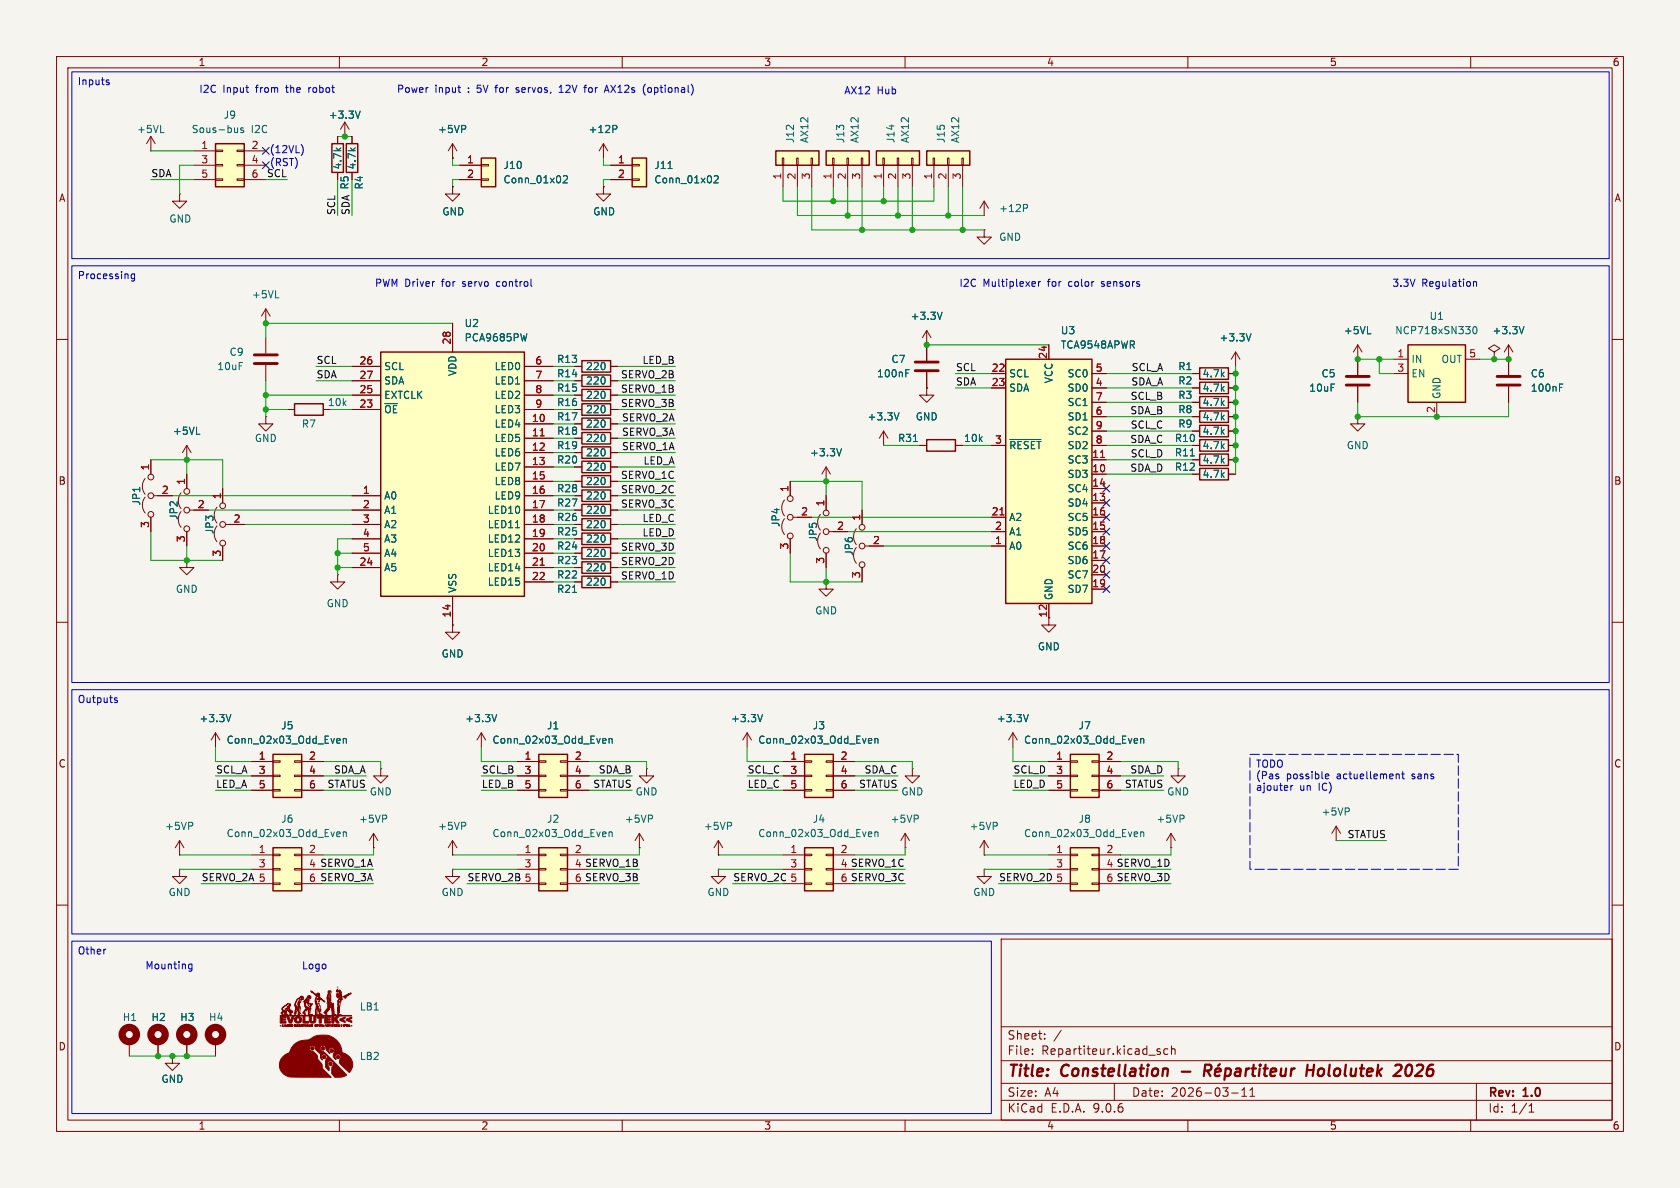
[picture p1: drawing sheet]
<svg xmlns="http://www.w3.org/2000/svg" width="297mm" height="210mm" viewBox="0 0 297 210" stroke-linecap="round" stroke-linejoin="round" font-family="sans-serif">
<defs><g id="words">
<g font-size="2.8" fill="#840000">
<text x="178" y="190.9">Title:</text>
<text x="187.7" y="190.9">Constellation</text>
<text x="233.4" y="190.9">Hololutek</text>
<text x="249.8" y="190.9">2026</text>
</g>
<g font-size="2.1" fill="#840000">
<text x="178" y="184">Sheet:</text>
<text x="178" y="186.7">File:</text>
<text x="184.1" y="186.7">Repartiteur.kicad_sch</text>
<text x="178" y="196.9">KiCad</text>
<text x="178" y="194.1">Size:</text>
<text x="184.7" y="194.1">A4</text>
<text x="185.7" y="196.9">E.D.A.</text>
<text x="193.3" y="196.9">9.0.6</text>
<text x="200" y="194.1">Date:</text>
<text x="207" y="194.1">2026-03-11</text>
<text x="263" y="194.3">Rev:</text>
<text x="263" y="196.9">Id:</text>
<text x="267.1" y="196.9">1/1</text>
<text x="269.4" y="194.3">1.0</text>
</g>
<g font-size="1.8" fill="#840000">
<text x="35" y="11.9">1</text>
<text x="85" y="11.9">2</text>
<text x="135" y="11.9">3</text>
<text x="185" y="11.9">4</text>
<text x="235" y="11.9">5</text>
<text x="285" y="11.9">6</text>
<text x="10.3" y="35.9">A</text>
<text x="285.3" y="35.9">A</text>
<text x="10.3" y="85.9">B</text>
<text x="285.3" y="85.9">B</text>
<text x="10.3" y="135.9">C</text>
<text x="285.3" y="135.9">C</text>
<text x="10.3" y="185.9">D</text>
<text x="285.3" y="185.9">D</text>
<text x="35" y="199.9">1</text>
<text x="85" y="199.9">2</text>
<text x="135" y="199.9">3</text>
<text x="185" y="199.9">4</text>
<text x="235" y="199.9">5</text>
<text x="285" y="199.9">6</text>
</g>
<g font-size="1.8" fill="#0000c2">
<text x="13.7" y="15.4">Inputs</text>
<text x="35.1" y="16.6">I2C</text>
<text x="39.4" y="16.6">Input</text>
<text x="45.3" y="16.6">from</text>
<text x="50.9" y="16.6">the</text>
<text x="55" y="16.6">robot</text>
<text x="70.1" y="16.6">Power</text>
<text x="76.9" y="16.6">input</text>
<text x="82.8" y="16.6">:</text>
<text x="84.6" y="16.6">5V</text>
<text x="88.1" y="16.6">for</text>
<text x="91.9" y="16.6">servos,</text>
<text x="99.7" y="16.6">12V</text>
<text x="104.4" y="16.6">for</text>
<text x="108.2" y="16.6">AX12s</text>
<text x="115.2" y="16.6">(optional)</text>
<text x="149.2" y="16.9">AX12</text>
<text x="155.1" y="16.9">Hub</text>
<text x="47.6" y="27.3">(12VL)</text>
<text x="47.6" y="29.6">(RST)</text>
<text x="47.1" y="31.4">SCL</text>
<text x="13.7" y="49.7">Processing</text>
<text x="66.2" y="50.9">PWM Driver</text>
<text x="78.2" y="50.9">for</text>
<text x="82" y="50.9">servo</text>
<text x="88.2" y="50.9">control</text>
<text x="169.5" y="50.9">I2C</text>
<text x="173.8" y="50.9">Multiplexer</text>
<text x="185.3" y="50.9">for</text>
<text x="189.2" y="50.9">color</text>
<text x="195.2" y="50.9">sensors</text>
<text x="246.1" y="50.9">3.3V</text>
<text x="251.3" y="50.9">Regulation</text>
<text x="13.7" y="124.6">Outputs</text>
<text x="221.9" y="136">TODO</text>
<text x="221.9" y="138.1">(Pas</text>
<text x="221.9" y="140.1">ajouter</text>
<text x="227.4" y="138.1">possible</text>
<text x="229.8" y="140.1">un</text>
<text x="233.2" y="140.1">IC)</text>
<text x="236.4" y="138.1">actuellement</text>
<text x="249.9" y="138.1">sans</text>
<text x="13.7" y="169">Other</text>
<text x="25.6" y="171.6">Mounting</text>
<text x="53.3" y="171.6">Logo</text>
</g>
<g font-size="1.8" fill="#006464">
<text x="24.1" y="23.7">+5VL</text>
<text x="33.8" y="23.7">Sous-bus</text>
<text x="39.4" y="21.2">J9</text>
<text x="44.4" y="23.7">I2C</text>
<text x="58" y="21.2">+3.3V</text>
<text x="77.3" y="23.7">+5VP</text>
<text x="103.9" y="23.7">+12P</text>
<text x="140.6" y="25.4" transform="rotate(-90 140.6 25.4)">J12</text>
<text x="143.1" y="25.4" transform="rotate(-90 143.1 25.4)">AX12</text>
<text x="149.5" y="25.4" transform="rotate(-90 149.5 25.4)">J13</text>
<text x="152" y="25.4" transform="rotate(-90 152 25.4)">AX12</text>
<text x="158.3" y="25.4" transform="rotate(-90 158.3 25.4)">J14</text>
<text x="160.9" y="25.4" transform="rotate(-90 160.9 25.4)">AX12</text>
<text x="167.2" y="25.4" transform="rotate(-90 167.2 25.4)">J15</text>
<text x="169.8" y="25.4" transform="rotate(-90 169.8 25.4)">AX12</text>
<text x="60.6" y="30.1" transform="rotate(-90 60.6 30.1)">4.7k</text>
<text x="61.8" y="33.6" transform="rotate(-90 61.8 33.6)">R5</text>
<text x="63.1" y="30.1" transform="rotate(-90 63.1 30.1)">4.7k</text>
<text x="64.4" y="33.6" transform="rotate(-90 64.4 33.6)">R4</text>
<text x="88.9" y="32.6">Conn_01x02</text>
<text x="88.9" y="30.1">J10</text>
<text x="115.6" y="32.6">Conn_01x02</text>
<text x="115.6" y="30.1">J11</text>
<text x="29.8" y="39.5">GND</text>
<text x="78.1" y="38.3">GND</text>
<text x="104.8" y="38.3">GND</text>
<text x="176.5" y="37.7">+12P</text>
<text x="176.5" y="42.8">GND</text>
<text x="44.4" y="52.9">+5VL</text>
<text x="82" y="58">U2</text>
<text x="160.9" y="56.7">+3.3V</text>
<text x="187.4" y="59.3">U3</text>
<text x="237.5" y="59.3">+5VL</text>
<text x="246.6" y="59.3">NCP718xSN330</text>
<text x="252.6" y="56.7">U1</text>
<text x="263.8" y="59.3">+3.3V</text>
<text x="38.3" y="65.6">10uF</text>
<text x="40.5" y="63.1">C9</text>
<text x="67.8" y="65.6">SCL</text>
<text x="82" y="60.6">PCA9685PW</text>
<text x="87.3" y="65.6">LED0</text>
<text x="98.4" y="64.4">R13</text>
<text x="103.5" y="65.6">220</text>
<text x="157.5" y="64.4">C7</text>
<text x="187.4" y="61.8">TCA9548APWR</text>
<text x="208.2" y="65.6">R1</text>
<text x="215.5" y="60.6">+3.3V</text>
<text x="249.4" y="64.4">IN</text>
<text x="254.7" y="64.4">OUT</text>
<text x="57.9" y="72">10k</text>
<text x="67.8" y="68.2">SDA</text>
<text x="67.8" y="70.7">EXTCLK</text>
<text x="80.9" y="66.6" transform="rotate(-90 80.9 66.6)">VDD</text>
<text x="87.3" y="68.2">LED1</text>
<text x="87.3" y="70.7">LED2</text>
<text x="98.4" y="69.4">R15</text>
<text x="98.4" y="66.9">R14</text>
<text x="98.4" y="72">R16</text>
<text x="103.5" y="70.7">220</text>
<text x="103.5" y="68.2">220</text>
<text x="154.9" y="66.9">100nF</text>
<text x="178.3" y="66.9">SCL</text>
<text x="178.3" y="69.4">SDA</text>
<text x="186.3" y="67.8" transform="rotate(-90 186.3 67.8)">VCC</text>
<text x="188.6" y="66.9">SC0</text>
<text x="188.6" y="69.4">SD0</text>
<text x="188.6" y="72">SC1</text>
<text x="208.2" y="70.7">R3</text>
<text x="208.2" y="68.2">R2</text>
<text x="212.5" y="72">4.7k</text>
<text x="212.5" y="69.4">4.7k</text>
<text x="212.5" y="66.9">4.7k</text>
<text x="231.4" y="69.4">10uF</text>
<text x="233.5" y="66.9">C5</text>
<text x="249.4" y="66.9">EN</text>
<text x="254.9" y="70.6" transform="rotate(-90 254.9 70.6)">GND</text>
<text x="270.5" y="66.9">C6</text>
<text x="270.5" y="69.4">100nF</text>
<text x="30.5" y="77.1">+5VL</text>
<text x="53.3" y="75.8">R7</text>
<text x="67.8" y="73.3">~{OE}</text>
<text x="87.3" y="73.3">LED3</text>
<text x="87.3" y="75.8">LED4</text>
<text x="98.4" y="74.5">R17</text>
<text x="98.4" y="77.1">R18</text>
<text x="103.5" y="75.8">220</text>
<text x="103.5" y="73.3">220</text>
<text x="153.3" y="74.5">+3.3V</text>
<text x="161.8" y="74.5">GND</text>
<text x="188.6" y="74.5">SD1</text>
<text x="188.6" y="77.1">SC2</text>
<text x="208.2" y="75.8">R9</text>
<text x="208.2" y="73.3">R8</text>
<text x="212.5" y="77.1">4.7k</text>
<text x="212.5" y="74.5">4.7k</text>
<text x="45" y="78.3">GND</text>
<text x="87.3" y="78.3">LED5</text>
<text x="87.3" y="80.9">LED6</text>
<text x="87.3" y="83.4">LED7</text>
<text x="98.4" y="82.1">R20</text>
<text x="98.4" y="79.6">R19</text>
<text x="103.5" y="83.4">220</text>
<text x="103.5" y="80.9">220</text>
<text x="103.5" y="78.3">220</text>
<text x="143.1" y="80.9">+3.3V</text>
<text x="158.7" y="78.3">R31</text>
<text x="170.3" y="78.3">10k</text>
<text x="178.3" y="79.6">~{RESET}</text>
<text x="188.6" y="79.6">SD2</text>
<text x="188.6" y="82.1">SC3</text>
<text x="207.6" y="80.9">R11</text>
<text x="207.6" y="83.4">R12</text>
<text x="207.6" y="78.3">R10</text>
<text x="212.5" y="82.1">4.7k</text>
<text x="212.5" y="79.6">4.7k</text>
<text x="238" y="79.6">GND</text>
<text x="25" y="89.5" transform="rotate(-90 25 89.5)">JP1</text>
<text x="67.8" y="88.5">A0</text>
<text x="87.3" y="86">LED8</text>
<text x="87.3" y="88.5">LED9</text>
<text x="98.4" y="87.2">R28</text>
<text x="98.4" y="89.8">R27</text>
<text x="103.5" y="86">220</text>
<text x="103.5" y="88.5">220</text>
<text x="188.6" y="84.7">SD3</text>
<text x="188.6" y="87.2">SC4</text>
<text x="188.6" y="89.8">SD4</text>
<text x="212.5" y="84.7">4.7k</text>
<text x="31.6" y="92" transform="rotate(-90 31.6 92)">JP2</text>
<text x="37.9" y="94.5" transform="rotate(-90 37.9 94.5)">JP3</text>
<text x="67.8" y="91">A1</text>
<text x="67.8" y="93.6">A2</text>
<text x="86.1" y="91">LED10</text>
<text x="86.1" y="93.6">LED11</text>
<text x="98.4" y="92.3">R26</text>
<text x="98.4" y="94.8">R25</text>
<text x="103.5" y="91">220</text>
<text x="103.5" y="93.6">220</text>
<text x="138" y="93.3" transform="rotate(-90 138 93.3)">JP4</text>
<text x="144.6" y="95.8" transform="rotate(-90 144.6 95.8)">JP5</text>
<text x="178.3" y="92.3">A2</text>
<text x="178.3" y="94.8">A1</text>
<text x="188.6" y="92.3">SC5</text>
<text x="188.6" y="94.8">SD5</text>
<text x="67.8" y="96.1">A3</text>
<text x="67.8" y="98.7">A4</text>
<text x="67.8" y="101.2">A5</text>
<text x="86.1" y="96.1">LED12</text>
<text x="86.1" y="98.7">LED13</text>
<text x="86.1" y="101.2">LED14</text>
<text x="98.4" y="99.9">R23</text>
<text x="98.4" y="97.4">R24</text>
<text x="103.5" y="101.2">220</text>
<text x="103.5" y="98.7">220</text>
<text x="103.5" y="96.1">220</text>
<text x="151" y="98.3" transform="rotate(-90 151 98.3)">JP6</text>
<text x="178.3" y="97.4">A0</text>
<text x="188.6" y="97.4">SC6</text>
<text x="188.6" y="99.9">SD6</text>
<text x="31" y="105">GND</text>
<text x="57.7" y="107.5">GND</text>
<text x="80.9" y="104.9" transform="rotate(-90 80.9 104.9)">VSS</text>
<text x="86.1" y="103.7">LED15</text>
<text x="98.4" y="105">R21</text>
<text x="98.4" y="102.5">R22</text>
<text x="103.5" y="103.7">220</text>
<text x="186.3" y="106.2" transform="rotate(-90 186.3 106.2)">GND</text>
<text x="188.6" y="102.5">SC7</text>
<text x="188.6" y="105">SD7</text>
<text x="144" y="108.8">GND</text>
<text x="78" y="116.4">GND</text>
<text x="183.4" y="115.2">GND</text>
<text x="35.2" y="127.9">+3.3V</text>
<text x="40" y="131.7">Conn_02x03_Odd_Even</text>
<text x="49.6" y="129.1">J5</text>
<text x="82.1" y="127.9">+3.3V</text>
<text x="87" y="131.7">Conn_02x03_Odd_Even</text>
<text x="96.6" y="129.1">J1</text>
<text x="129.1" y="127.9">+3.3V</text>
<text x="133.9" y="131.7">Conn_02x03_Odd_Even</text>
<text x="143.6" y="129.1">J3</text>
<text x="176.1" y="127.9">+3.3V</text>
<text x="180.9" y="131.7">Conn_02x03_Odd_Even</text>
<text x="190.6" y="129.1">J7</text>
<text x="65.3" y="140.8">GND</text>
<text x="112.3" y="140.8">GND</text>
<text x="159.3" y="140.8">GND</text>
<text x="206.2" y="140.8">GND</text>
<text x="29.1" y="146.9">+5VP</text>
<text x="40" y="148.2">Conn_02x03_Odd_Even</text>
<text x="49.6" y="145.6">J6</text>
<text x="63.4" y="145.6">+5VP</text>
<text x="77.3" y="146.9">+5VP</text>
<text x="87" y="148.2">Conn_02x03_Odd_Even</text>
<text x="96.6" y="145.6">J2</text>
<text x="110.4" y="145.6">+5VP</text>
<text x="124.3" y="146.9">+5VP</text>
<text x="133.9" y="148.2">Conn_02x03_Odd_Even</text>
<text x="143.6" y="145.6">J4</text>
<text x="157.3" y="145.6">+5VP</text>
<text x="171.3" y="146.9">+5VP</text>
<text x="180.9" y="148.2">Conn_02x03_Odd_Even</text>
<text x="190.6" y="145.6">J8</text>
<text x="204.3" y="145.6">+5VP</text>
<text x="233.5" y="144.4">+5VP</text>
<text x="29.7" y="158.6">GND</text>
<text x="78" y="158.6">GND</text>
<text x="125" y="158.6">GND</text>
<text x="172" y="158.6">GND</text>
<text x="63.5" y="178.8">LB1</text>
<text x="21.6" y="180.7">H1</text>
<text x="26.7" y="180.7">H2</text>
<text x="31.8" y="180.7">H3</text>
<text x="36.8" y="180.7">H4</text>
<text x="28.4" y="191.6">GND</text>
<text x="63.5" y="187.6">LB2</text>
</g>
<g font-size="1.8" fill="#a90000">
<text x="35.5" y="26.4">1</text>
<text x="35.5" y="29">3</text>
<text x="44.4" y="26.4">2</text>
<text x="44.4" y="29">4</text>
<text x="82.5" y="29">1</text>
<text x="109.1" y="29">1</text>
<text x="35.5" y="31.5">5</text>
<text x="44.4" y="31.5">6</text>
<text x="82.5" y="31.5">2</text>
<text x="109.1" y="31.5">2</text>
<text x="138.2" y="31.8" transform="rotate(-90 138.2 31.8)">1</text>
<text x="140.7" y="31.8" transform="rotate(-90 140.7 31.8)">2</text>
<text x="143.3" y="31.8" transform="rotate(-90 143.3 31.8)">3</text>
<text x="147.1" y="31.8" transform="rotate(-90 147.1 31.8)">1</text>
<text x="149.6" y="31.8" transform="rotate(-90 149.6 31.8)">2</text>
<text x="152.1" y="31.8" transform="rotate(-90 152.1 31.8)">3</text>
<text x="156" y="31.8" transform="rotate(-90 156 31.8)">1</text>
<text x="158.5" y="31.8" transform="rotate(-90 158.5 31.8)">2</text>
<text x="161" y="31.8" transform="rotate(-90 161 31.8)">3</text>
<text x="164.8" y="31.8" transform="rotate(-90 164.8 31.8)">1</text>
<text x="167.4" y="31.8" transform="rotate(-90 167.4 31.8)">2</text>
<text x="169.9" y="31.8" transform="rotate(-90 169.9 31.8)">3</text>
<text x="63.5" y="64.5">26</text>
<text x="79.8" y="61" transform="rotate(-90 79.8 61)">28</text>
<text x="94.5" y="64.5">6</text>
<text x="175.2" y="65.8">22</text>
<text x="185.2" y="63.5" transform="rotate(-90 185.2 63.5)">24</text>
<text x="193.6" y="65.8">5</text>
<text x="246.9" y="63.2">1</text>
<text x="246.9" y="65.8">3</text>
<text x="259.6" y="63.2">5</text>
<text x="63.5" y="67.1">27</text>
<text x="63.5" y="69.6">25</text>
<text x="94.5" y="67.1">7</text>
<text x="94.5" y="69.6">8</text>
<text x="175.2" y="68.3">23</text>
<text x="193.6" y="68.3">4</text>
<text x="193.6" y="70.9">7</text>
<text x="63.5" y="72.1">23</text>
<text x="93.9" y="74.7">10</text>
<text x="93.9" y="77.2">11</text>
<text x="94.5" y="72.1">9</text>
<text x="193.6" y="73.4">6</text>
<text x="193.6" y="75.9">9</text>
<text x="253.7" y="73.1" transform="rotate(-90 253.7 73.1)">2</text>
<text x="26.4" y="83.3" transform="rotate(-90 26.4 83.3)">1</text>
<text x="93.9" y="79.8">12</text>
<text x="93.9" y="82.3">13</text>
<text x="175.8" y="78.5">3</text>
<text x="193" y="81">11</text>
<text x="193" y="83.6">10</text>
<text x="193.6" y="78.5">8</text>
<text x="28.5" y="87.4">2</text>
<text x="32.8" y="85.8" transform="rotate(-90 32.8 85.8)">1</text>
<text x="34.9" y="89.9">2</text>
<text x="39.1" y="88.3" transform="rotate(-90 39.1 88.3)">1</text>
<text x="64.1" y="87.4">1</text>
<text x="64.1" y="89.9">2</text>
<text x="93.9" y="84.8">15</text>
<text x="93.9" y="87.4">16</text>
<text x="93.9" y="89.9">17</text>
<text x="139.4" y="87.1" transform="rotate(-90 139.4 87.1)">1</text>
<text x="145.8" y="89.6" transform="rotate(-90 145.8 89.6)">1</text>
<text x="193" y="86.1">14</text>
<text x="193" y="88.6">13</text>
<text x="26.4" y="93.4" transform="rotate(-90 26.4 93.4)">3</text>
<text x="32.8" y="96" transform="rotate(-90 32.8 96)">3</text>
<text x="41.2" y="92.5">2</text>
<text x="64.1" y="92.5">3</text>
<text x="64.1" y="95">4</text>
<text x="93.9" y="92.5">18</text>
<text x="93.9" y="95">19</text>
<text x="141.5" y="91.2">2</text>
<text x="147.9" y="93.7">2</text>
<text x="152.1" y="92.1" transform="rotate(-90 152.1 92.1)">1</text>
<text x="175.2" y="91.2">21</text>
<text x="175.8" y="93.7">2</text>
<text x="193" y="91.2">16</text>
<text x="193" y="93.7">15</text>
<text x="39.1" y="98.5" transform="rotate(-90 39.1 98.5)">3</text>
<text x="63.5" y="100.1">24</text>
<text x="64.1" y="97.5">5</text>
<text x="93.9" y="97.5">20</text>
<text x="93.9" y="100.1">21</text>
<text x="139.4" y="97.2" transform="rotate(-90 139.4 97.2)">3</text>
<text x="145.8" y="99.8" transform="rotate(-90 145.8 99.8)">3</text>
<text x="154.2" y="96.3">2</text>
<text x="175.8" y="96.3">1</text>
<text x="193" y="96.3">18</text>
<text x="193" y="98.8">17</text>
<text x="193" y="101.3">20</text>
<text x="93.9" y="102.6">22</text>
<text x="152.1" y="102.3" transform="rotate(-90 152.1 102.3)">3</text>
<text x="193" y="103.9">19</text>
<text x="79.8" y="109.3" transform="rotate(-90 79.8 109.3)">14</text>
<text x="185.2" y="109.3" transform="rotate(-90 185.2 109.3)">12</text>
<text x="45.6" y="134.4">1</text>
<text x="45.6" y="136.9">3</text>
<text x="54.5" y="134.4">2</text>
<text x="54.5" y="136.9">4</text>
<text x="92.6" y="134.4">1</text>
<text x="92.6" y="136.9">3</text>
<text x="101.5" y="134.4">2</text>
<text x="101.5" y="136.9">4</text>
<text x="139.6" y="134.4">1</text>
<text x="139.6" y="136.9">3</text>
<text x="148.5" y="134.4">2</text>
<text x="148.5" y="136.9">4</text>
<text x="186.6" y="134.4">1</text>
<text x="186.6" y="136.9">3</text>
<text x="195.5" y="134.4">2</text>
<text x="195.5" y="136.9">4</text>
<text x="45.6" y="139.4">5</text>
<text x="54.5" y="139.4">6</text>
<text x="92.6" y="139.4">5</text>
<text x="101.5" y="139.4">6</text>
<text x="139.6" y="139.4">5</text>
<text x="148.5" y="139.4">6</text>
<text x="186.6" y="139.4">5</text>
<text x="195.5" y="139.4">6</text>
<text x="45.6" y="150.9">1</text>
<text x="45.6" y="153.4">3</text>
<text x="54.5" y="150.9">2</text>
<text x="92.6" y="150.9">1</text>
<text x="92.6" y="153.4">3</text>
<text x="101.5" y="150.9">2</text>
<text x="139.6" y="150.9">1</text>
<text x="139.6" y="153.4">3</text>
<text x="148.5" y="150.9">2</text>
<text x="186.6" y="150.9">1</text>
<text x="186.6" y="153.4">3</text>
<text x="195.5" y="150.9">2</text>
</g>
<g font-size="1.8" fill="#0f0f0f">
<text x="26.7" y="31.4">SDA</text>
<text x="59.3" y="38.1" transform="rotate(-90 59.3 38.1)">SCL</text>
<text x="61.9" y="38.1" transform="rotate(-90 61.9 38.1)">SDA R5</text>
<text x="55.9" y="64.4">SCL</text>
<text x="113.5" y="64.4">LED_B</text>
<text x="168.9" y="65.7">SCL</text>
<text x="200" y="65.7">SCL_A</text>
<text x="55.9" y="67">SDA</text>
<text x="109.7" y="69.5">SERVO_1B</text>
<text x="109.7" y="67">SERVO_2B</text>
<text x="168.9" y="68.2">SDA</text>
<text x="199.8" y="70.8">SCL_B</text>
<text x="199.9" y="68.2">SDA_A</text>
<text x="109.7" y="72">SERVO_3B</text>
<text x="109.9" y="77.1">SERVO_3A</text>
<text x="109.9" y="74.6">SERVO_2A</text>
<text x="199.7" y="73.3">SDA_B</text>
<text x="199.8" y="75.9">SCL_C</text>
<text x="109.9" y="79.7">SERVO_1A</text>
<text x="113.7" y="82.2">LED_A</text>
<text x="199.7" y="83.5">SDA_D</text>
<text x="199.7" y="78.4">SDA_C</text>
<text x="199.8" y="80.9">SCL_D</text>
<text x="109.7" y="89.8">SERVO_3C</text>
<text x="109.7" y="84.7">SERVO_1C</text>
<text x="109.7" y="87.3">SERVO_2C</text>
<text x="113.5" y="92.4">LED_C</text>
<text x="113.5" y="94.9">LED_D</text>
<text x="109.7" y="97.4">SERVO_3D</text>
<text x="109.7" y="100">SERVO_2D</text>
<text x="109.7" y="102.5">SERVO_1D</text>
<text x="38.1" y="136.8">SCL_A</text>
<text x="58.9" y="136.8">SDA_A</text>
<text x="85.1" y="136.8">SCL_B</text>
<text x="105.8" y="136.8">SDA_B</text>
<text x="132.1" y="136.8">SCL_C</text>
<text x="152.7" y="136.8">SDA_C</text>
<text x="179.1" y="136.8">SCL_D</text>
<text x="199.7" y="136.8">SDA_D</text>
<text x="38.1" y="139.4">LED_A</text>
<text x="57.8" y="139.4">STATUS</text>
<text x="85.1" y="139.4">LED_B</text>
<text x="104.8" y="139.4">STATUS</text>
<text x="132.1" y="139.4">LED_C</text>
<text x="151.8" y="139.4">STATUS</text>
<text x="179.1" y="139.4">LED_D</text>
<text x="198.8" y="139.4">STATUS</text>
<text x="238.1" y="148.2">STATUS</text>
<text x="35.6" y="155.9">SERVO_2A 5</text>
<text x="54.5" y="153.4">4 SERVO_1A</text>
<text x="54.5" y="156">6 SERVO_3A</text>
<text x="82.5" y="155.9">SERVO_2B 5</text>
<text x="101.5" y="153.4">4 SERVO_1B</text>
<text x="101.5" y="156">6 SERVO_3B</text>
<text x="129.5" y="155.9">SERVO_2C 5</text>
<text x="148.5" y="153.4">4 SERVO_1C</text>
<text x="148.5" y="156">6 SERVO_3C</text>
<text x="176.5" y="155.9">SERVO_2D 5</text>
<text x="195.5" y="153.4">4 SERVO_1D</text>
<text x="195.5" y="156">6 SERVO_3D</text>
</g>
</g></defs>
<path d="M0 0h297v210h-297z" fill="#f5f4ef" stroke="#f5f4ef" stroke-width=".18"/>
<g fill="none" stroke="#840000" stroke-width=".18">
<path d="M10 10h277v190h-277zM12 12h273v186h-273zM60 10v2M110 10v2M160 10v2M210 10v2M260 10v2M10 60h2M101.6 64.8h1.3M107.9 64.8h1.3M156.2 76.2l-.8 1.3M156.2 76.2l.8 1.3"/>
<path d="M156.2 76.2v2.5M264.2 62.2l1-.6-1-.6-1.1 .6 1.1 .6v1.3M264.2 63.5h.1M266.7 61l-.8 1.2M266.7 61l.8 1.2M266.7 61v2.5M285 60h2M10 110h2M59.7 101.6v1.3h1.3l-1.3 1.2-1.3-1.2h1.3M59.7 101.6h.1M285 110h2M207 149.9h.1"/>
<path d="M207 147.3l-.8 1.3M207 147.3l.8 1.3M207 147.3v2.6M10 160h2M177 166h108v32h-108zM285 160h2M60 198v2M110 198v2M160 198v2M177 194.5h108M177 191.5h108M177 187.5h108"/>
<path d="M177 181.5h108M182.5 186.3v.1M182.5 185.5v.1M184.7 183.6v.1M184.7 182.8v.1M187.6 182.1l-1.3 2M197 191.5v3M204.7 185.9l.4 .1 .1 .2-.2 .2h-.3M204.7 185.4l.4 .1M206.5 185.5l-.5-.1-.3 .3v.4l.2 .2h.6M207.1 185.5l.2-.1 .4 .1v.9M207.1 184.9v1.5"/>
<path d="M210 198v2M217.7 193.2h1.2M219.5 193.8h.9M219.5 192.7l.5-.4v1.5M221 193.8h.8M221 192.7l.4-.4v1.5M260 198v2M261 191.5v6.5M270.3 196.6h.9M270.3 195.5l.4-.4v1.5"/>
</g>
<g fill="none" stroke="#840000" stroke-width=".4">
<path d="M206.2 188.9l.3 .3-.2 1M208.9 189.4h1.5M212.9 189.3h.8a.55 .55 0 0 0 .5-.5 .55 .55 0 0 0-.4-.6h-.7l-.3 2M213.4 189.3l.6 .9M214.8 189.5l1-.1-.1-.4-.1-.1-.6 .1-.2 .9 .2 .3 .6-.1M215.7 188.1l-.4 .3M216.7 189l.2-.1 .6 .1 .1 .3-.1 .5a.66 .66 0 0 1-.9 .3M216.7 188.9l-.2 2M218.5 189l.2-.1 .6 .1-.1 1.2M219.3 189.4h-.7a.4 .4 0 0 0-.3 .4 .4 .4 0 0 0 .2 .4l.7-.1M220.3 188.9l-.1 1.3M220.9 188.9l-.4 .1-.2 .3"/>
<path d="M221.3 188.9h.7M221.6 188.2l-.2 1.7 .1 .2 .4 .1M222.7 188.9l-.2 1.3M222.8 188.2v.2M222.8 188.2l-.1 .1 .1 .1M222.8 188.2l.1 .1-.1 .1M223.4 188.9h.7M223.7 188.2l-.2 1.7 .1 .2 .4 .1M224.6 189.5l1-.1v-.4l-.2-.1-.6 .1-.2 .9 .2 .3 .6-.1M226.5 188.9v1.2a.57 .57 0 0 0 .7-.1M227.4 188.9l-.2 1.3M228.3 188.9l-.1 1.3"/>
<path d="M228.9 188.9l-.4 .1-.2 .3M231.1 189.2h1.1M231.2 188.2l-.3 2M232.3 188.2l-.2 2M247 188.2h.5a.45 .45 0 0 1 .3 .6l-.2 .3-1.3 1.1h1.3M249.1 188.2a1.41 1.41 0 0 0-.5 1.9l.4 .1"/>
</g>
<path d="M269.4 57.7l-.4 1.3M158.9 73l-.4 1.2M209.2 144.2l.1 .1-.1 .4" fill="none" stroke="#006464" stroke-width=".18"/>
<path d="M102.9 63.8h5v2h-5z" fill="none" stroke="#840000" stroke-width=".25"/>
<path d="M67.3 62.2h25.4v43.2h-25.4z" fill="#ffffc2"/>
<path d="M52.1 71.4h5v2h-5zM67.3 62.2h25.4v43.2h-25.4zM212.1 77.7h5.1v2.1h-5.1zM212.1 75.2h5.1v2h-5.1zM212.1 72.6h5.1v2.1h-5.1zM212.1 70.1h5.1v2h-5.1zM212.1 67.6h5.1v2h-5.1zM212.1 65h5.1v2.1h-5.1zM212.1 80.3h5.1v2h-5.1zM212.1 82.8h5.1v2h-5.1z" fill="none" stroke="#840000" stroke-width=".25"/>
<g fill="none" stroke="#840000" stroke-width=".18">
<path d="M31.7 34.3v1.3h1.3l-1.3 1.2-1.2-1.2h1.2M31.7 34.3h.1M47 59.7v2.8M80 57.2v5M47 73.7v1.2h1.3l-1.3 1.3-1.3-1.3h1.3M47 73.7h.1M47 64.5v2.8M50.8 72.4h1.3M57.1 72.4h1.3M62.2 64.8h5.1M62.2 67.3h5.1M62.2 69.9h5.1"/>
<path d="M62.2 72.4h5.1M92.7 64.8h5.1M92.7 67.3h5.1M92.7 69.9h5.1M92.7 72.4h5.1M92.7 74.9h5.1M92.7 77.5h5.1M210.8 78.7h1.3M210.8 76.2h1.3M210.8 73.7h1.3M210.8 71.1h1.3M210.8 68.6h1.3"/>
<path d="M210.8 66h1.3M217.2 78.7h1.2M217.2 76.2h1.2M217.2 73.7h1.2M217.2 71.1h1.2M217.2 68.6h1.2M217.2 66h1.2M218.4 62.2l-.7 1.3M218.4 62.2l.8 1.3M218.4 62.2v2.6M38.4 89.7a2.26 2.26 0 0 0 0 2.8M38.4 93a2.26 2.26 0 0 0 0 2.8"/>
<path d="M39.4 86.4v2.5M39.4 96.5v2.6M39.9 92.7h3.3M62.2 87.6h5.1M62.2 90.2h5.1M62.2 92.7h5.1M62.2 95.3h5.1M62.2 97.8h5.1M92.7 87.6h5.1M92.7 90.2h5.1M92.7 92.7h5.1M92.7 95.3h5.1"/>
<path d="M92.7 97.8h5.1M92.7 80h5.1M92.7 82.6h5.1M92.7 85.1h5.1M145 90.9a2.26 2.26 0 0 0 0 2.8M145 94.2a2.26 2.26 0 0 0 0 2.8M146 87.6v2.6M146 97.8v2.5M146.6 94h3.3M210.8 81.3h1.3M210.8 83.8h1.3M217.2 81.3h1.2"/>
<path d="M217.2 83.8h1.2M62.2 100.3h5.1M80 105.4v5.1M92.7 100.3h5.1M92.7 102.9h5.1M161.3 135.9v1.3h1.3l-1.3 1.2-1.3-1.2h1.3M161.3 135.9h.1"/>
<circle cx="39.4" cy="92.7" r=".51"/>
<circle cx="39.4" cy="89.4" r=".51"/>
<circle cx="39.4" cy="96" r=".51"/>
<circle cx="146.1" cy="90.7" r=".51"/>
<circle cx="146.1" cy="94" r=".51"/>
<circle cx="146.1" cy="97.3" r=".51"/>
</g>
<path d="M95.5 77.1h.7M95.5 99.9h.7" fill="none" stroke="#a90000" stroke-width=".18"/>
<path d="M93.1 59l-.3 1.3M221.2 59l-.5 1.3M91.1 93.3h.8M210.4 80.6h.8" fill="none" stroke="#006464" stroke-width=".18"/>
<path d="M45 64.3h4M45 62.7h4" fill="none" stroke="#840000" stroke-width=".51"/>
<path d="M38.1 25.4h5.1v7.6h-5.1z" fill="#ffffc2"/>
<path d="M38.1 25.4h5.1v7.6h-5.1z" fill="none" stroke="#840000" stroke-width=".25"/>
<g fill="none" stroke="#840000" stroke-width=".18">
<path d="M26.7 26.7h.1M26.7 24.1l-.8 1.3M26.7 24.1l.7 1.3M26.7 24.1v2.6M34.3 26.7h3.8M34.3 29.2h3.8M34.3 31.8h3.8M38.1 26.5h1.3v.3h-1.3zM38.1 29.1h1.3v.2h-1.3zM38.1 31.6h1.3v.3h-1.3zM41.9 26.5h1.3v.3h-1.3zM41.9 29.1h1.3v.2h-1.3z"/>
<path d="M41.9 31.6h1.3v.3h-1.3zM43.2 26.7h3.8M43.2 29.2h3.8M43.2 31.8h3.8M240 63.5h.1M240 61l-.7 1.2M240 61l.8 1.2M240 61v5.3M240 68.3v2.8M160 149.9h.1M160 147.3l-.7 1.3M160 147.3l.8 1.3"/>
<path d="M160 147.3v2.6"/>
</g>
<path d="M28.4 23.4h.6M42 22.6v.8M42 23.3l-.2 .1M43 22.7l-.3-.1-.2 .2 .1 .2 .4 .1v.3h-.5M241.8 59h.6M162.2 144.2l.1 .1-.1 .4" fill="none" stroke="#006464" stroke-width=".18"/>
<path d="M238 66.5h4.1M238 68.1h4.1" fill="none" stroke="#840000" stroke-width=".51"/>
<path d="M137.2 26.7h7.6v2.5h-7.6z" fill="#ffffc2"/>
<path d="M137.2 26.7h7.6v2.5h-7.6z" fill="none" stroke="#840000" stroke-width=".25"/>
<path d="M138.3 27.9h.3v1.3h-.3zM138.4 29.2v3.8M140.8 27.9h.3v1.3h-.3zM141 29.2v3.8M143.4 27.9h.2v1.3h-.2zM143.5 29.2v3.8" fill="none" stroke="#840000" stroke-width=".18"/>
<path d="M146 26.7h7.7v2.5h-7.7z" fill="#ffffc2"/>
<path d="M58.7 25.4h2v5.1h-2zM146 26.7h7.7v2.5h-7.7z" fill="none" stroke="#840000" stroke-width=".25"/>
<g fill="none" stroke="#840000" stroke-width=".18">
<path d="M59.7 24.1v1.3M59.7 30.5v1.3M80 33v1.3h1.3l-1.3 1.3-1.3-1.3h1.3M80 33h.1M80 27.9h.1M80 25.4l-.8 1.3M80 25.4l.8 1.3M80 25.4v2.5M106.7 25.4l-.8 1.3M106.7 25.4l.7 1.3M106.7 25.4v2.5M147.2 27.9h.2v1.3h-.2z"/>
<path d="M147.3 29.2v3.8M149.7 27.9h.3v1.3h-.3zM149.9 29.2v3.8M152.3 27.9h.2v1.3h-.2zM152.4 29.2v3.8M138.7 88.4a2.26 2.26 0 0 0 0 2.8M138.7 91.7a2.26 2.26 0 0 0 0 2.8M139.7 85.1v2.5M139.7 95.3v2.5M140.2 91.4h3.3M185.4 109.2v1.3h1.3l-1.3 1.3-1.3-1.3h1.3M38.1 129.5l-.8 1.3"/>
<path d="M38.1 129.5l.8 1.3M38.1 129.5v2.6M85.1 129.5l-.8 1.3M85.1 129.5l.8 1.3M85.1 129.5v2.6"/>
<circle cx="139.7" cy="88.1" r=".51"/>
<circle cx="139.7" cy="91.4" r=".51"/>
<circle cx="139.7" cy="94.7" r=".51"/>
</g>
<path d="M82.2 22.2l.1 .2-.1 .4M108.3 22.2h.5l.3 .2-.2 .4h-.6M40.8 126.3l-.4 1.3M87.8 126.3l-.4 1.3" fill="none" stroke="#006464" stroke-width=".18"/>
<path d="M111.8 27.9h2.5v5.1h-2.5z" fill="#ffffc2"/>
<path d="M61.2 25.4h2v5.1h-2zM111.8 27.9h2.5v5.1h-2.5z" fill="none" stroke="#840000" stroke-width=".25"/>
<g fill="none" stroke="#840000" stroke-width=".18">
<path d="M62.2 24.1v1.3M62.2 30.5v1.3M106.7 33v1.3h1.2l-1.2 1.3-1.3-1.3h1.3M106.7 33h.1M107.9 29.2h3.9M107.9 31.8h3.9M111.8 29.1h1.2v.2h-1.2zM111.8 31.6h1.2v.3h-1.2zM163.8 58.4l-.7 1.3M163.8 58.4l.8 1.3M163.8 58.4v5.4M33 78.7v2.6"/>
<path d="M33 78.7l-.7 1.3M33 78.7l.8 1.3M163.8 68.6v1.3h1.3l-1.3 1.2-1.2-1.2h1.2M163.8 68.6h.1M163.8 65.8v2.8M25.7 84.6a2.26 2.26 0 0 0 0 2.8M25.7 87.9a2.26 2.26 0 0 0 0 2.8M26.7 81.3v2.5M26.7 91.4v2.6M27.2 87.6h3.3M32 87.1a2.26 2.26 0 0 0 0 2.8M32 90.4a2.26 2.26 0 0 0 0 2.8"/>
<path d="M33 81.3h.1M33 99.1v1.2h1.3l-1.3 1.3-1.3-1.3h1.3M33 99.1h.1M33 83.8v2.6M33 94v2.5M33.5 90.2h3.3M146 102.9v1.2h1.3l-1.3 1.3-1.2-1.3h1.2M146 102.9h.1M179.1 129.5l-.8 1.3M179.1 129.5l.7 1.3M179.1 129.5v2.6M31.7 151.1h.1"/>
<path d="M31.7 153.7v1.2h1.3l-1.3 1.3-1.2-1.3h1.2M31.7 153.7h.1M31.7 148.6l-.7 1.3M31.7 148.6l.8 1.3M31.7 148.6v2.5M66 149.9h.1M66 147.3l-.7 1.3M66 147.3l.8 1.3M66 147.3v2.6M80 153.7v1.2h1.3l-1.3 1.3-1.3-1.3h1.3M80 153.7h.1M174 151.1h.1"/>
<path d="M174 148.6l-.8 1.3M174 148.6l.8 1.3M174 148.6v2.5M27.9 184.2v2.5M38.1 184.2v2.5"/>
<circle cx="26.7" cy="84.3" r=".51"/>
<circle cx="26.7" cy="87.6" r=".51"/>
<circle cx="26.7" cy="90.9" r=".51"/>
<circle cx="33" cy="86.9" r=".51"/>
<circle cx="33" cy="93.5" r=".51"/>
<circle cx="33" cy="90.2" r=".51"/>
</g>
<path d="M118.1 29.8h.7M126.3 31.2l.4-.1 .3 .3-.8 .9h.8M166.6 55.2l-.5 1.3M34.7 76.8h.6M160.1 66h.5M160.1 65.3h.6M181.8 126.3l-.4 1.3M34 145.4l.1 .2-.1 .4M68.2 144.2l.2 .1-.2 .4M176.2 145.4l.1 .2-.1 .4" fill="none" stroke="#006464" stroke-width=".18"/>
<g fill="none" stroke="#840000" stroke-width="1.3">
<circle cx="27.9" cy="182.9" r="1.27"/>
<circle cx="38.1" cy="182.9" r="1.27"/>
</g>
<path d="M161.8 64h4.1M161.8 65.5h4.1" fill="none" stroke="#840000" stroke-width=".51"/>
<path d="M48.3 149.9h5v7.6h-5z" fill="#ffffc2"/>
<path d="M163.8 77.7h5.1v2.1h-5.1zM102.9 99.3h5v2h-5zM102.9 96.8h5v2h-5zM102.9 101.9h5v2h-5zM48.3 149.9h5v7.6h-5z" fill="none" stroke="#840000" stroke-width=".25"/>
<g fill="none" stroke="#840000" stroke-width=".18">
<path d="M162.6 78.7h1.2M168.9 78.7h1.3M101.6 97.8h1.3M107.9 97.8h1.3M101.6 102.9h1.3M101.6 100.3h1.3M107.9 102.9h1.3M107.9 100.3h1.3M44.4 151.1h3.9M44.4 153.7h3.9M44.4 156.2h3.9M48.3 151h1.2v.3h-1.2z"/>
<path d="M48.3 153.5h1.2v.3h-1.2zM48.3 156.1h1.2v.2h-1.2zM52.1 151h1.2v.3h-1.2zM52.1 153.5h1.2v.3h-1.2zM52.1 156.1h1.2v.2h-1.2zM53.3 151.1h3.8M53.3 153.7h3.8M53.3 156.2h3.8M33 184.2v2.5"/>
</g>
<path d="M161.5 78h.7M101.2 104.7h.7M59.7 147.1h.4v.3l-.6 .1M60.1 147.8l-.4 .1M60.7 147.2l.2-.1h.3v.8M60.7 147.1v.8" fill="none" stroke="#006464" stroke-width=".18"/>
<circle cx="33" cy="182.9" r="1.27" fill="none" stroke="#840000" stroke-width="1.3"/>
<path d="M163.8 26.7h7.6v2.5h-7.6z" fill="#ffffc2"/>
<path d="M163.8 26.7h7.6v2.5h-7.6zM102.9 89.2h5v2h-5zM102.9 94.2h5v2.1h-5zM102.9 91.7h5v2h-5z" fill="none" stroke="#840000" stroke-width=".25"/>
<g fill="none" stroke="#840000" stroke-width=".18">
<path d="M165 27.9h.2v1.3h-.2zM165.1 29.2v3.8M167.5 27.9h.3v1.3h-.3zM167.6 29.2v3.8M170.1 27.9h.2v1.3h-.2zM170.2 29.2v3.8M174 35.6l-.8 1.2M174 35.6l.8 1.2M174 35.6v2.5M174 40.6v1.3h1.3l-1.3 1.3-1.3-1.3h1.3M174 40.6h.1M101.6 90.2h1.3"/>
<path d="M101.6 95.3h1.3M101.6 92.7h1.3M107.9 90.2h1.3M107.9 95.3h1.3M107.9 92.7h1.3M127 153.7v1.2h1.3l-1.3 1.3-1.3-1.3h1.3M127 153.7h.1M22.9 184.2v2.5M30.5 186.7v1.3h1.2l-1.2 1.2-1.3-1.2h1.3M30.5 186.7h.1"/>
</g>
<path d="M180.9 36.1h.5l.3 .3-.2 .3-.6 .1" fill="none" stroke="#006464" stroke-width=".18"/>
<g fill="#840000" stroke="#840000" stroke-width=".18">
<path d="M49.6 181.3h.1z"/>
<path d="M49.9 179.2l.1 .1z"/>
<path d="M49.9 181.1l.2 .3-.2 .1z"/>
<path d="M50.2 181.2h.1z"/>
<path d="M50.4 181.2h.2l.1 .3-.4-.1 .1-.1h.1h-.1z"/>
<path d="M50.4 178.3l.1 .1 .2-.2-.2 .3z"/>
<path d="M49.6 179.7h1v.2h-.7v.2h.6v.2h-.6v.3h.7v.3h-1.1z"/>
<path d="M50 178.1l1-.7-.3 .2a1.04 1.04 0 0 0-.7 .9l.5 .2-.1 .6h.5l-.6 .1 .1-.6-.2 .1 .1-.1h-.2a.27 .27 0 0 0-.2 .2 .27 .27 0 0 0 0 .3h.2a.27 .27 0 0 1-.3 0 .27 .27 0 0 1 0-.3 .31 .31 0 0 0 .2-.3 .31 .31 0 0 0-.2-.3z"/>
<path d="M50.5 178.5l.1 .6z"/>
<path d="M50.8 181.2h.2h-.2l.2 .2h-.2h.1z"/>
<path d="M51 177.8l.1 .2z"/>
<path d="M51.1 178.1v.2z"/>
<path d="M51.1 177.9l.1 .5z"/>
<path d="M51.1 181.2l.2-.1-.1 .1 .2 .1a.15 .15 0 0 1-.1 .2 .15 .15 0 0 1-.2-.1h.2z"/>
<path d="M51.1 177.6l.2 .2h-.2h.2z"/>
<path d="M50.8 177.9l.1 .1a.9 .9 0 0 0 .4 1l.1 .3h-.2v-.3a.85 .85 0 0 1-.4-1z"/>
<path d="M50.7 179.7h.4l.3 .8 .2-.8h.4l-.4 1.1a.45 .45 0 0 1-.5 0 .45 .45 0 0 1-.2-.5z"/>
<path d="M51.2 177.4l.2 .3z"/>
<path d="M51.3 178.8l.1 .1z"/>
<path d="M51.5 179.3h-.1z"/>
<path d="M51.5 179v.1z"/>
<path d="M51.5 181.2a.18 .18 0 0 1 .3 0 .18 .18 0 0 1-.1 .3 .18 .18 0 0 1-.3-.2h.3l-.1-.1-.2 .1z"/>
<path d="M51.1 178.4l.6 .6-.4-.3v.1z"/>
<path d="M51.7 178.8v.1z"/>
<path d="M52 181.1l.3 .1v.3l-.1-.2-.1 .2-.1-.3h.2z"/>
<path d="M52.5 178.7l-.1 .2z"/>
<path d="M52.6 178.5l-.1 .1z"/>
<path d="M52.5 181.1h.1a.18 .18 0 0 1 .2 .2 .18 .18 0 0 1-.2 .2 .18 .18 0 0 1-.2-.2h.2v-.1l-.2 .1z"/>
<path d="M53 176.6v.1a1.36 1.36 0 0 0-.2 1.3l-.1-.7z"/>
<path d="M52.2 179.8a.65 .65 0 0 1 1.1 .1 .65 .65 0 0 1-.5 1 .65 .65 0 0 1-.7-.7h.3v.1a.27 .27 0 0 0 .4 .3 .27 .27 0 0 0 .1-.4 .26 .26 0 0 0-.2-.3 .26 .26 0 0 0-.3 .3h-.3z"/>
<path d="M52.5 176.7a.74 .74 0 0 1 .8-.3v-.1h-.3h.1a.28 .28 0 0 1 .3-.2 .28 .28 0 0 1 .2 .3l-.1-.1h-.1l.2 .4-.3-.1a.33 .33 0 0 0-.3-.2 .33 .33 0 0 0-.3 .2l-.1 .1a.87 .87 0 0 0 0 1.3 .52 .52 0 0 1 .2 .7l.1 .7h-.1l-.1-.9a.37 .37 0 0 0-.4 .1 .37 .37 0 0 0 0 .4l-.1 .3h-.1l.2-1h.4h-.4l-.1-.5 .5 .5-.5-.5-.1-.2z"/>
<path d="M52.8 181.1l.3 .1v.2l-.3 .1v-.1h.2h-.2v-.2h.2z"/>
<path d="M53.1 177.1l-.2 .8a.56 .56 0 0 1 .2-.8z"/>
<path d="M52.9 177.9l.1 .1z"/>
<path d="M53 178.8v.2z"/>
<path d="M52.9 177.9l.2 .1z"/>
<path d="M53 178.6v.1z"/>
<path d="M53 179.1l.1 .1z"/>
<path d="M53.2 181.2a.18 .18 0 0 1 .3 0 .18 .18 0 0 1-.1 .3 .18 .18 0 0 1-.2-.2l.2 .1v-.2z"/>
<path d="M53.6 181.2h.3l-.1 .2z"/>
<path d="M53.9 178.9v.3z"/>
<path d="M54 181.1v.4z"/>
<path d="M54.1 178.7l.2-.1z"/>
<path d="M54.2 181.1a.21 .21 0 0 1 .3 .1 .21 .21 0 0 1 0 .2h-.3v-.1h.2l-.1-.1-.1 .1z"/>
<path d="M54.5 177.6v.1z"/>
<path d="M53.6 179.7h.3v.9h.6v.3l-.9-.1z"/>
<path d="M54.6 176.6l-.1 .1z"/>
<path d="M54.5 176.8v.2l.1-.1v.3z"/>
<path d="M54.5 177.7l.1 .1z"/>
<path d="M54.6 176.7v.1z"/>
<path d="M54.8 179v.1z"/>
<path d="M54.6 177.9l.2 .1z"/>
<path d="M54.6 181.1l.1 .3 .1-.3a.19 .19 0 0 1 .1 .3 .19 .19 0 0 1-.3 0 .19 .19 0 0 1 0-.3z"/>
<path d="M55 177.6l-.1 .3z"/>
<path d="M54.8 178.1l.2 .2z"/>
<path d="M54.4 176.1a.32 .32 0 0 1 .5 .1v-.1l-.1 .1 .1 .3h-.2v-.3l-.1 .2h-.3a.71 .71 0 0 0 .1 .8 .71 .71 0 0 0 .6 .3l.2 .1-.7-.1-.3-.2v-.6l-.1 .7a.56 .56 0 0 0 .4 .7 .46 .46 0 0 1 .1 .7 .4 .4 0 0 0 .1 .5 .4 .4 0 0 0 .5 0l-.7 .1 .1-1-.1-.2-.1 .2a.78 .78 0 0 0-.7 .8l.3 .1a.33 .33 0 0 1-.4-.2 .33 .33 0 0 1 .2-.4l.1-.2a.24 .24 0 0 0 .2-.1 .24 .24 0 0 0-.1-.3l.4 .1-.4-.1-.1-.2 .3 .2v-.1a.57 .57 0 0 1-.4-.7l-.1-.3 .2 .4 .1-.6-.3 .2z"/>
<path d="M55.1 177.4h.1z"/>
<path d="M55 181.1l.3 .1h-.2l.1 .1-.1 .1h.2l-.3 .1z"/>
<path d="M54.7 179.7h.3l.1 .8a.21 .21 0 0 0 .2 .1 .21 .21 0 0 0 .2-.2v-.7h.4l-.1 .4a.6 .6 0 0 1-.6 .8 .6 .6 0 0 1-.5-.8z"/>
<path d="M55.7 181.1l.3 .1h-.2l.2 .1-.2 .1h.1l-.2 .1z"/>
<path d="M56 177v.2z"/>
<path d="M56 178.9v.1z"/>
<path d="M56.1 176.7l-.1 .1z"/>
<path d="M56.1 178.7v.1z"/>
<path d="M56.1 176.5v.1z"/>
<path d="M56 181.1l.3 .1-.2 .3-.1-.3h.2z"/>
<path d="M56 177.4l.1 .1z"/>
<path d="M56.4 176.9v.2z"/>
<path d="M56.3 177.4h.1z"/>
<path d="M56.4 181.1v.4z"/>
<path d="M56.7 178.3v.5z"/>
<path d="M56.6 181.2h.3l-.1 .2z"/>
<path d="M56.1 179.7h1.1v.3h-.4v.9l-.4-.1v-.8h-.4z"/>
<path d="M49.5 179.6h12.6z"/>
<path d="M54.9 175.1l1 .8h.3h-.3a.3 .3 0 0 1 .3-.3 .3 .3 0 0 1 .3 .3l-.2-.2v.3h.2a.3 .3 0 0 0 .2 .5h.1l.6 .6-.6-.5-.4 .2v-.4l.1 .3 .2-.1-.4-.3-.1-.3a1.12 1.12 0 0 0 0 1.7l-.1 .1 .3 .5 .1 1 .5 .1h-.6l-.1-1.2a.7 .7 0 0 0-.4 1v.1l.3 .1-.5-.1 .1-.6 .1-.5h.4h-.4v-.3h.3v.2v-.2h-.3v-.1a1.72 1.72 0 0 1 0-1.7v-.1h.6h-.6z"/>
<path d="M57 181.2l.2 .2h-.3v-.1h.2h-.2z"/>
<path d="M57.5 181.1l-.1 .4z"/>
<path d="M57.8 181.1l.2 .1h-.1l.1 .1-.1 .1h.1l-.2 .1z"/>
<path d="M58.1 181.1l.3 .1-.2 .3-.1-.3h.2h-.2z"/>
<path d="M58 175.2h.4l.1 .1h-.3v.4l-.2-.2z"/>
<path d="M58.2 176v.1z"/>
<path d="M58.1 176.2l.3 .7-.2 .1-.1-.6z"/>
<path d="M57.4 179.7h1v.2h-.6v.2h.6v.2h-.6v.3h.6v.3h-1z"/>
<path d="M58.3 175.7h.1l.1 .4v.8z"/>
<path d="M58.5 181.1v.4z"/>
<path d="M58.5 177.2l.2 .4z"/>
<path d="M58.7 181.2h.3l-.2 .2z"/>
<path d="M58.9 177.3l.1 1-.3-.6 .1 .1z"/>
<path d="M59 178.4v.2z"/>
<path d="M59 178.7v.1z"/>
<path d="M59.1 179v.1z"/>
<path d="M59 181.1l.3 .1h-.2l.2 .1-.2 .1h.2l-.3 .1z"/>
<path d="M58 175.7l-.1 .9 .2 .8h.1v-.3h.2l-.1 .1a2.08 2.08 0 0 1 .6 2l.5 .3h-.7l-.1-1.3-.3-.3-.1 .5-.5 .6h-.1l.2 .3a.41 .41 0 0 1-.5-.4l.4-.4h.4l.2-.3v-.3l-.2 .6h-.4l.2-.3v-1.3a.89 .89 0 0 1 .1-1.1z"/>
<path d="M59.7 174.9l-.1 .4z"/>
<path d="M59.4 181.2l.3-.1-.2 .2 .2 .1a.18 .18 0 0 1-.3 0 .18 .18 0 0 1 0-.2z"/>
<path d="M58.7 179.7h.3v.4l.1-.1a.55 .55 0 0 1 .8-.3l-.1 .2a.32 .32 0 0 0-.3 .2 .32 .32 0 0 0 .2 .4l.2 .3-.1 .1a.47 .47 0 0 1-.6-.5l-.2 .2v.3l-.3-.1z"/>
<path d="M59.7 175.1h.1z"/>
<path d="M59.8 181.2h.1l.2-.1v.3l-.2-.1-.1 .1z"/>
<path d="M59.6 175.5v.3a.29 .29 0 0 0 .2 .5v-.5l.2 .4a.53 .53 0 0 1-.2 .7l.2 .2h-.1l-.1 .8 .3-.1-.1 1.2v-1a.16 .16 0 0 0-.2 .1 .16 .16 0 0 0 .1 .2h-.1v1.1h.5l-.6 .1 .1-2.6a.4 .4 0 0 0 .1-.6 .2 .2 0 0 1-.3 0 .2 .2 0 0 1-.1-.2z"/>
<path d="M60 175.7l.1 .2z"/>
<path d="M60.1 177.6v.1z"/>
<path d="M59.9 175.1l.5 .4-.1 .1-.3-.3 .1 .3-.1 .1v.3l.3 .6 .2 .1-.2-.1-.1 .5-.1 .1v-.1h.1v-.4l-.3-.9 .1-.2z"/>
<path d="M60.1 177.4v.1z"/>
<path d="M60 175.3l.1 .3z"/>
<path d="M60.1 175.6l.1 .4-.1-.1z"/>
<path d="M60.1 175.1l.1 .1z"/>
<path d="M60.2 175.2l.1 .1z"/>
<path d="M60.4 181.1l-.1 .4z"/>
<path d="M60.3 175.8l.1 .7z"/>
<path d="M60.7 181.1v.4z"/>
<path d="M60.7 176.2l1-.6-.9 .6z"/>
<path d="M60.8 181.1l.3 .1-.2 .3-.1-.3h.2z"/>
<path d="M60.1 180.1l.9-.3v.3l-.5 .2 .5 .2v.2l-.9-.3z"/>
<path d="M60.9 176.3l1.1-.8v.2l-.5 .3a.42 .42 0 0 0-.5 .4l.2-.1-.2 .1z"/>
<path d="M61.2 181.1l.3 .1h-.2l.2 .2h-.3h.2z"/>
<path d="M61.7 181.1l.2 .4h-.4l.1-.2h.1h-.1z"/>
<path d="M61.2 180.1l1-.3a.3 .3 0 0 1-.1 .3 .3 .3 0 0 1-.3 .1l-.2 .1 .6 .2v.3l-1-.4z"/>
<path d="M62.1 181.3h.1z"/>
<path d="M51.9 184.7a4.1 4.1 0 0 1 2.7-.9 3.9 3.9 0 0 1 4.8 0 4.6 4.6 0 0 1 1.2 2.3 2.04 2.04 0 0 1 1.6 1.4 2.04 2.04 0 0 1-.5 2.1l-.6-.6a2.08 2.08 0 0 1-1.1-1.3l.1-.3a.55 .55 0 0 0-.1-1 .55 .55 0 0 0-.8 .6l.2 .3a.86 .86 0 0 1-.2-1.4 .53 .53 0 0 0-.6-.7 .53 .53 0 0 0-.4 .8l.1 .3-.6-.7a.6 .6 0 0 0-.3-.7 .6 .6 0 0 0-.7 .1 .62 .62 0 0 0 .5 .9l4.1 4.1-.9 .4h-1.2a1.24 1.24 0 0 1-.5-1.5v-.3a.57 .57 0 0 0 .2-.9 .57 .57 0 0 0-.9 0 .57 .57 0 0 0 .1 .9l.1 .6a1.46 1.46 0 0 1-.6-1.7v-.1a.57 .57 0 0 0 .2-.9 .57 .57 0 0 0-.9 0 .57 .57 0 0 0 .1 .9 .77 .77 0 0 1-.3-1.1l-.9-.9a.56 .56 0 0 0-.6-.6 .56 .56 0 0 0-.5 .6 .56 .56 0 0 0 .7 .5 1.51 1.51 0 0 1 .8 1.4l.2 .2a1.36 1.36 0 0 1 .6 1.3l1.6 1.6h-5.8a3.5 3.5 0 0 1-2.7-.6 2.19 2.19 0 0 1 1-3.7z"/>
<circle cx="55.2" cy="185.3" r=".32"/>
<circle cx="57.1" cy="185.3" r=".31"/>
<circle cx="57.3" cy="186.9" r=".31"/>
<circle cx="58.4" cy="188.1" r=".32"/>
<circle cx="58.6" cy="185.7" r=".3"/>
<circle cx="59.7" cy="186.8" r=".31"/>
</g>
<circle cx="22.9" cy="182.9" r="1.27" fill="none" stroke="#840000" stroke-width="1.3"/>
<path d="M142.2 149.9h5.1v7.6h-5.1z" fill="#ffffc2"/>
<path d="M102.9 84.1h5v2h-5zM102.9 86.6h5v2h-5zM102.9 81.5h5v2.1h-5zM142.2 149.9h5.1v7.6h-5.1z" fill="none" stroke="#840000" stroke-width=".25"/>
<g fill="none" stroke="#840000" stroke-width=".18">
<path d="M101.6 85.1h1.3M101.6 87.6h1.3M101.6 82.6h1.3M107.9 85.1h1.3M107.9 87.6h1.3M107.9 82.6h1.3M114.3 135.9v1.3h1.3l-1.3 1.2-1.3-1.2h1.3M114.3 135.9h.1M132.1 129.5l-.8 1.3M132.1 129.5l.7 1.3M132.1 129.5v2.6M113 149.9h.1"/>
<path d="M113 147.3l-.7 1.3M113 147.3l.8 1.3M113 147.3v2.6M127 151.1h.1M127 148.6l-.8 1.3M127 148.6l.8 1.3M127 148.6v2.5M138.4 151.1h3.8M138.4 153.7h3.8M138.4 156.2h3.8M142.2 151h1.3v.3h-1.3zM142.2 153.5h1.3v.3h-1.3z"/>
<path d="M142.2 156.1h1.3v.2h-1.3zM146 151h1.3v.3h-1.3zM146 153.5h1.3v.3h-1.3zM146 156.1h1.3v.2h-1.3zM147.3 151.1h3.8M147.3 153.7h3.8M147.3 156.2h3.8"/>
</g>
<path d="M134.8 126.3l-.4 1.3M115.2 144.2l.2 .1-.2 .4M129.2 145.4l.1 .2-.1 .4M153.7 147.1h.4v.3l-.6 .1M154.1 147.8l-.4 .1M154.7 147.2l.1-.1h.4v.8M154.7 147.1v.8" fill="none" stroke="#006464" stroke-width=".18"/>
<path d="M95.2 149.9h5.1v7.6h-5.1z" fill="#ffffc2"/>
<path d="M102.9 68.8h5v2.1h-5zM102.9 66.3h5v2h-5zM102.9 79h5v2h-5zM102.9 73.9h5v2h-5zM102.9 71.4h5v2h-5zM102.9 76.5h5v2h-5zM95.2 149.9h5.1v7.6h-5.1z" fill="none" stroke="#840000" stroke-width=".25"/>
<g fill="none" stroke="#840000" stroke-width=".18">
<path d="M101.6 69.9h1.3M101.6 67.3h1.3M101.6 74.9h1.3M101.6 72.4h1.3M101.6 77.5h1.3M107.9 69.9h1.3M107.9 67.3h1.3M107.9 74.9h1.3M107.9 72.4h1.3M107.9 77.5h1.3M101.6 80h1.3M107.9 80h1.3"/>
<path d="M146 82.6l-.7 1.2M146 82.6l.8 1.2M146 82.6v2.5M151.4 93.5a2.26 2.26 0 0 0 0 2.8M151.4 96.8a2.26 2.26 0 0 0 0 2.8M152.4 90.2v2.5M152.9 96.5h3.3M80 110.5v1.3h1.3l-1.3 1.2-1.3-1.2h1.3M80 110.5h.1M152.4 100.3v2.6M80 151.1h.1M80 148.6l-.8 1.3"/>
<path d="M80 148.6l.8 1.3M80 148.6v2.5M91.4 151.1h3.8M91.4 153.7h3.8M91.4 156.2h3.8M95.2 151h1.3v.3h-1.3zM95.2 153.5h1.3v.3h-1.3zM95.2 156.1h1.3v.2h-1.3zM99.1 151h1.2v.3h-1.2zM99.1 153.5h1.2v.3h-1.2zM99.1 156.1h1.2v.2h-1.2zM100.3 151.1h3.8"/>
<path d="M100.3 153.7h3.8M100.3 156.2h3.8"/>
<circle cx="152.4" cy="93.2" r=".51"/>
<circle cx="152.4" cy="96.5" r=".51"/>
<circle cx="152.4" cy="99.8" r=".51"/>
</g>
<path d="M148.8 79.3l-.5 1.3M82.2 145.4l.1 .2-.1 .4M106.7 147.1h.4v.3l-.6 .1M107.1 147.8l-.4 .1M107.7 147.2l.2-.1h.3v.8M107.7 147.1v.8" fill="none" stroke="#006464" stroke-width=".18"/>
<path d="M189.2 133.4h5.1v7.6h-5.1z" fill="#ffffc2"/>
<path d="M189.2 133.4h5.1v7.6h-5.1z" fill="none" stroke="#840000" stroke-width=".25"/>
<g fill="none" stroke="#840000" stroke-width=".18">
<path d="M185.4 134.6h3.8M185.4 137.2h3.8M185.4 139.7h3.8M189.2 134.5h1.3v.2h-1.3zM189.2 137h1.3v.3h-1.3zM189.2 139.6h1.3v.2h-1.3zM193 134.5h1.3v.2h-1.3zM193 137h1.3v.3h-1.3zM193 139.6h1.3v.2h-1.3zM194.3 134.6h3.8M194.3 137.2h3.8M194.3 139.7h3.8"/>
<path d="M208.3 135.9v1.3h1.2l-1.2 1.2-1.3-1.2h1.3M208.3 135.9h.1M236.2 148.6h.1M236.2 146.1l-.7 1.2M236.2 146.1l.8 1.2M236.2 146.1v2.5"/>
</g>
<path d="M200.7 130.5l.4 .1v.2l-.6 .2M201.1 131.3l-.4 .1M201.7 130.7l.1-.2 .3 .1 .1 .8M201.7 130.5v.9M238.4 142.9l.1 .2-.1 .3" fill="none" stroke="#006464" stroke-width=".18"/>
<path d="M154.9 26.7h7.7v2.5h-7.7z" fill="#ffffc2"/>
<path d="M154.9 26.7h7.7v2.5h-7.7z" fill="none" stroke="#840000" stroke-width=".25"/>
<path d="M156.1 27.9h.2v1.3h-.2zM156.2 29.2v3.8M158.6 27.9h.3v1.3h-.3zM158.7 29.2v3.8M161.2 27.9h.2v1.3h-.2zM161.3 29.2v3.8" fill="none" stroke="#840000" stroke-width=".18"/>
<path d="M177.8 63.5h15.2v43.2h-15.2z" fill="#ffffc2"/>
<path d="M177.8 63.5h15.2v43.2h-15.2z" fill="none" stroke="#840000" stroke-width=".25"/>
<g fill="none" stroke="#840000" stroke-width=".18">
<path d="M175.3 66h2.5M175.3 68.6h2.5M175.3 78.7h2.5M185.4 61v2.5M193 66h2.6M193 68.6h2.6M193 78.7h2.6M193 71.1h2.6M193 73.7h2.6M193 76.2h2.6M175.3 91.4h2.5M175.3 94h2.5"/>
<path d="M175.3 96.5h2.5M193 91.4h2.6M193 94h2.6M193 96.5h2.6M193 81.3h2.6M193 83.8h2.6M193 86.4h2.6M193 88.9h2.6M193 99.1h2.6M185.4 106.7v2.5M193 101.6h2.6M193 104.1h2.6"/>
</g>
<path d="M178.5 77.7h5.5" fill="none" stroke="#006464" stroke-width=".18"/>
<path d="M176.8 91h.7M194.6 80.9h.7" fill="none" stroke="#a90000" stroke-width=".18"/>
<path d="M142.2 133.4h5.1v7.6h-5.1z" fill="#ffffc2"/>
<path d="M142.2 133.4h5.1v7.6h-5.1z" fill="none" stroke="#840000" stroke-width=".25"/>
<path d="M138.4 134.6h3.8M138.4 137.2h3.8M138.4 139.7h3.8M142.2 134.5h1.3v.2h-1.3zM142.2 137h1.3v.3h-1.3zM142.2 139.6h1.3v.2h-1.3zM146 134.5h1.3v.2h-1.3zM146 137h1.3v.3h-1.3zM146 139.6h1.3v.2h-1.3zM147.3 134.6h3.8M147.3 137.2h3.8M147.3 139.7h3.8" fill="none" stroke="#840000" stroke-width=".18"/>
<path d="M153.7 130.5l.4 .1v.2l-.6 .2M154.1 131.3l-.4 .1M154.7 130.7l.1-.2 .4 .1v.8M154.7 130.5v.9" fill="none" stroke="#006464" stroke-width=".18"/>
<path d="M85.1 27.9h2.5v5.1h-2.5z" fill="#ffffc2"/>
<path d="M85.1 27.9h2.5v5.1h-2.5z" fill="none" stroke="#840000" stroke-width=".25"/>
<path d="M61 21.6l-.8 1.3M61 21.6l.7 1.3M61 21.6v2.5M81.3 29.2h3.8M81.3 31.8h3.8M85.1 29.1h1.3v.2h-1.3zM85.1 31.6h1.3v.3h-1.3zM47 57.2h.1M47 54.6l-.8 1.3M47 54.6l.8 1.3M47 54.6v2.6" fill="none" stroke="#840000" stroke-width=".18"/>
<path d="M63.7 19.6l-.4 1.3M99.6 31.2l.5-.1 .2 .3-.8 .9h.8M48.7 52.6h.6" fill="none" stroke="#006464" stroke-width=".18"/>
<path d="M48.3 133.4h5v7.6h-5z" fill="#ffffc2"/>
<path d="M48.3 133.4h5v7.6h-5z" fill="none" stroke="#840000" stroke-width=".25"/>
<g fill="none" stroke="#840000" stroke-width=".18">
<path d="M44.4 134.6h3.9M44.4 137.2h3.9M44.4 139.7h3.9M48.3 134.5h1.2v.2h-1.2zM48.3 137h1.2v.3h-1.2zM48.3 139.6h1.2v.2h-1.2zM52.1 134.5h1.2v.2h-1.2zM52.1 137h1.2v.3h-1.2zM52.1 139.6h1.2v.2h-1.2zM53.3 134.6h3.8M53.3 137.2h3.8M53.3 139.7h3.8"/>
<path d="M174 153.7v1.2h1.3l-1.3 1.3-1.3-1.3h1.3M174 153.7h.1"/>
</g>
<path d="M59.7 130.5l.4 .1v.2l-.6 .2M60.1 131.3l-.4 .1M60.7 130.7l.2-.2 .3 .1v.8M60.7 130.5v.9" fill="none" stroke="#006464" stroke-width=".18"/>
<path d="M189.2 149.9h5.1v7.6h-5.1z" fill="#ffffc2"/>
<path d="M189.2 149.9h5.1v7.6h-5.1z" fill="none" stroke="#840000" stroke-width=".25"/>
<path d="M185.4 151.1h3.8M185.4 153.7h3.8M185.4 156.2h3.8M189.2 151h1.3v.3h-1.3zM189.2 153.5h1.3v.3h-1.3zM189.2 156.1h1.3v.2h-1.3zM193 151h1.3v.3h-1.3zM193 153.5h1.3v.3h-1.3zM193 156.1h1.3v.2h-1.3zM194.3 151.1h3.8M194.3 153.7h3.8M194.3 156.2h3.8" fill="none" stroke="#840000" stroke-width=".18"/>
<path d="M200.7 147.1h.4v.3l-.6 .1M201.1 147.8l-.4 .1M201.7 147.2l.1-.1h.3l.1 .8M201.7 147.1v.8" fill="none" stroke="#006464" stroke-width=".18"/>
<path d="M95.2 133.4h5.1v7.6h-5.1z" fill="#ffffc2"/>
<path d="M95.2 133.4h5.1v7.6h-5.1z" fill="none" stroke="#840000" stroke-width=".25"/>
<g fill="none" stroke="#840000" stroke-width=".18">
<path d="M67.3 135.9v1.3h1.3l-1.3 1.2-1.3-1.2h1.3M67.3 135.9h.1M91.4 134.6h3.8M91.4 137.2h3.8M91.4 139.7h3.8M95.2 134.5h1.3v.2h-1.3zM95.2 137h1.3v.3h-1.3zM95.2 139.6h1.3v.2h-1.3zM99.1 134.5h1.2v.2h-1.2zM99.1 137h1.2v.3h-1.2zM99.1 139.6h1.2v.2h-1.2zM100.3 134.6h3.8"/>
<path d="M100.3 137.2h3.8M100.3 139.7h3.8"/>
</g>
<path d="M106.7 130.5l.4 .1v.2l-.6 .2M107.1 131.3l-.4 .1M107.7 130.7l.2-.2 .3 .1v.8M107.7 130.5v.9" fill="none" stroke="#006464" stroke-width=".18"/>
<path d="M248.9 61h10.2v10.1h-10.2z" fill="#ffffc2"/>
<path d="M248.9 61h10.2v10.1h-10.2z" fill="none" stroke="#840000" stroke-width=".25"/>
<g fill="none" stroke="#840000" stroke-width=".18">
<path d="M59.7 24.1v1.3M59.7 30.5v1.3M62.2 24.1v1.3M62.2 30.5v1.3M80 33h.1M80 27.9h.1M81.3 29.2h3.8M81.3 31.8h3.8M106.7 33h.1M107.9 29.2h3.9M107.9 31.8h3.9M80 57.2v5"/>
<path d="M62.2 69.9h5.1M62.2 67.3h5.1M62.2 72.4h5.1M62.2 64.8h5.1M92.7 69.9h5.1M92.7 67.3h5.1M92.7 74.9h5.1M92.7 72.4h5.1M92.7 77.5h5.1M92.7 64.8h5.1M101.6 69.9h1.3M101.6 67.3h1.3"/>
<path d="M101.6 74.9h1.3M101.6 72.4h1.3M101.6 77.5h1.3M101.6 64.8h1.3M107.9 69.9h1.3M107.9 67.3h1.3M107.9 74.9h1.3M107.9 72.4h1.3M107.9 77.5h1.3M107.9 64.8h1.3M162.6 78.7h1.2M163.8 68.6h.1"/>
<path d="M163.8 61v2.8M163.8 65.8v2.8M168.9 78.7h1.3M175.3 66h2.5M175.3 78.7h2.5M175.3 68.6h2.5M185.4 61v2.5M193 66h2.6M193 78.7h2.6M193 76.2h2.6M193 73.7h2.6M193 71.1h2.6"/>
<path d="M193 68.6h2.6M210.8 66h1.3M210.8 78.7h1.3M210.8 76.2h1.3M210.8 73.7h1.3M210.8 71.1h1.3M210.8 68.6h1.3M217.2 66h1.2M217.2 78.7h1.2M217.2 76.2h1.2M217.2 73.7h1.2M217.2 71.1h1.2"/>
<path d="M217.2 68.6h1.2M240 73.7v1.2h1.3l-1.3 1.3-1.2-1.3h1.2M240 73.7h.1M240 63.5h.1M240 63.5v2.8M240 68.3v2.8M246.4 63.5h2.5M246.4 66h2.5M254 71.1v2.6M259.1 63.5h2.5M264.2 63.5h.1M266.7 63.5v2.8"/>
<path d="M266.7 68.3v2.8M26.7 81.3v2.5M26.7 91.4v2.6M27.9 87.6h2.6M33 81.3h.1M33 83.8v2.6M33 94v2.5M34.3 90.2h2.5M39.4 86.4v2.5M39.4 96.5v2.6M40.6 92.7h2.6M62.2 87.6h5.1"/>
<path d="M62.2 97.8h5.1M62.2 90.2h5.1M62.2 95.3h5.1M62.2 92.7h5.1M92.7 85.1h5.1M92.7 87.6h5.1M92.7 82.6h5.1M92.7 80h5.1M92.7 97.8h5.1M92.7 90.2h5.1M92.7 95.3h5.1M92.7 92.7h5.1"/>
<path d="M101.6 85.1h1.3M101.6 87.6h1.3M101.6 82.6h1.3M101.6 80h1.3M101.6 97.8h1.3M101.6 90.2h1.3M101.6 95.3h1.3M101.6 92.7h1.3M107.9 85.1h1.3M107.9 87.6h1.3M107.9 82.6h1.3M107.9 80h1.3"/>
<path d="M107.9 97.8h1.3M107.9 90.2h1.3M107.9 95.3h1.3M107.9 92.7h1.3M139.7 85.1v2.5M139.7 95.3v2.5M141 91.4h2.5M146 87.6v2.6M146 97.8v2.5M147.3 94h2.6M152.4 90.2v2.5M153.7 96.5h2.5"/>
<path d="M175.3 91.4h2.5M175.3 94h2.5M175.3 96.5h2.5M193 81.3h2.6M193 83.8h2.6M193 91.4h2.6M193 94h2.6M193 96.5h2.6M193 86.4h2.6M193 88.9h2.6M193 99.1h2.6M210.8 81.3h1.3"/>
<path d="M210.8 83.8h1.3M217.2 81.3h1.2M217.2 83.8h1.2M62.2 100.3h5.1M80 110.5h.1M80 105.4v5.1M92.7 102.9h5.1M92.7 100.3h5.1M101.6 102.9h1.3M101.6 100.3h1.3M107.9 102.9h1.3M107.9 100.3h1.3"/>
<path d="M152.4 100.3v2.6M185.4 106.7v2.5M193 101.6h2.6M193 104.1h2.6M44.4 134.6h3.9M44.4 137.2h3.9M44.4 139.7h3.9M53.3 134.6h3.8M53.3 137.2h3.8M53.3 139.7h3.8M91.4 134.6h3.8M91.4 137.2h3.8"/>
<path d="M91.4 139.7h3.8M100.3 134.6h3.8M100.3 137.2h3.8M100.3 139.7h3.8M138.4 134.6h3.8M138.4 137.2h3.8M138.4 139.7h3.8M147.3 134.6h3.8M147.3 137.2h3.8M147.3 139.7h3.8M185.4 134.6h3.8M185.4 137.2h3.8"/>
<path d="M185.4 139.7h3.8M194.3 134.6h3.8M194.3 137.2h3.8M194.3 139.7h3.8M27.9 184.2v2.5M30.5 186.7h.1M33 184.2v2.5"/>
</g>
<g fill="none" stroke="#006464" stroke-width=".18">
<path d="M63.7 19.6l-.4 1.3M82.2 22.2l.1 .2-.1 .4M99.6 31.2l.5-.1 .2 .3-.8 .9h.8M108.3 22.2h.5l.3 .2-.2 .4h-.6M118.1 29.8h.7M126.3 31.2l.4-.1 .3 .3-.8 .9h.8M93.1 59l-.3 1.3M166.6 55.2l-.5 1.3M221.2 59l-.5 1.3M241.8 59h.6M260.5 57.9l.2-.2a.68 .68 0 0 1 .4 .7 .68 .68 0 0 1-.4 .6l-.2-.1-.1-.4zM269.4 57.7l-.4 1.3"/>
<path d="M34.7 76.8h.6M148.8 79.3l-.5 1.3M158.9 73l-.4 1.2M160.1 66h.5M160.1 65.3h.6M161.5 78h.7M178.5 77.7h5.5M275.7 68.5h.4M275.7 67.9h.6M91.1 93.3h.8M210.4 80.6h.8M101.2 104.7h.7"/>
<path d="M40.8 126.3l-.4 1.3M59.7 130.5l.4 .1v.2l-.6 .2M60.1 131.3l-.4 .1M60.7 130.7l.2-.2 .3 .1v.8M60.7 130.5v.9M87.8 126.3l-.4 1.3M106.7 130.5l.4 .1v.2l-.6 .2M107.1 131.3l-.4 .1M107.7 130.7l.2-.2 .3 .1v.8M107.7 130.5v.9M134.8 126.3l-.4 1.3M153.7 130.5l.4 .1v.2l-.6 .2"/>
<path d="M154.1 131.3l-.4 .1M154.7 130.7l.1-.2 .4 .1v.8M154.7 130.5v.9M181.8 126.3l-.4 1.3M200.7 130.5l.4 .1v.2l-.6 .2M201.1 131.3l-.4 .1M201.7 130.7l.1-.2 .3 .1 .1 .8M201.7 130.5v.9"/>
</g>
<path d="M264.7 66.5h4M264.7 68.1h4" fill="none" stroke="#840000" stroke-width=".51"/>
<g fill="none" stroke="#009600" stroke-width=".18">
<path d="M26.7 31.8h7.6M26.7 26.7h7.6M34.3 29.2h-2.6v5.1M47 31.8h3.8M59.7 31.8v6.3M59.7 24.1h2.5M62.2 31.8v6.3M80 27.9v1.3h1.3M81.3 31.8h-1.3v1.2M106.7 27.9v1.3h1.2M107.9 31.8h-1.2v1.2M138.4 33v2.6h26.7v-2.6"/>
<path d="M141 33v5.1h33M143.5 33v7.6h30.5M147.3 33v2.6M149.9 33v5.1M152.4 33v7.6M156.2 33v2.6M158.7 33v5.1M161.3 33v7.6M167.6 33v5.1M170.2 33v7.6M80 57.2h-33v2.5M47 67.3v6.4"/>
<path d="M47 72.4h3.8M47 69.9h15.2M55.9 67.3h6.3M55.9 64.8h6.3M58.4 72.4h3.8M97.8 72.4h3.8M97.8 67.3h3.8M97.8 64.8h3.8M97.8 69.9h3.8M97.8 74.9h3.8M97.8 77.5h3.8M109.2 72.4h10.2"/>
<path d="M109.2 67.3h10.2M109.2 64.8h10.2M109.2 69.9h10.2M109.2 74.9h10.2M109.2 77.5h10.2M156.2 78.7h6.4M163.8 61h21.6M168.9 66h6.4M168.9 68.6h6.4M170.2 78.7h5.1M195.6 66h15.2M195.6 78.7h15.2"/>
<path d="M195.6 68.6h15.2M195.6 71.1h15.2M195.6 73.7h15.2M195.6 76.2h15.2M218.4 64.8v19M240 71.1v2.6h26.7v-2.6M240 63.5h6.4M243.8 63.5v2.5h2.6M261.6 63.5h5.1M26.7 94v5.1h12.7M26.7 81.3h12.7v5.1M30.5 87.6h31.7"/>
<path d="M33 81.3v2.5M33 96.5v2.6M36.8 90.2h25.4M43.2 92.7h19M59.7 97.8h2.5M62.2 95.3h-2.5v6.3M97.8 87.6h3.8M97.8 97.8h3.8M97.8 95.3h3.8M97.8 92.7h3.8M97.8 85.1h3.8M97.8 90.2h3.8"/>
<path d="M97.8 82.6h3.8M97.8 80h3.8M109.2 87.6h10.2M109.2 97.8h10.2M109.2 95.3h10.2M109.2 92.7h10.2M109.2 85.1h10.2M109.2 90.2h10.2M109.2 82.6h10.2M109.2 80h10.2M139.7 85.1h12.7v5.1M139.7 97.8v5.1h12.7"/>
<path d="M143.5 91.4h31.8M146 85.1v2.5M149.9 94h25.4M156.2 96.5h19.1M195.6 81.3h15.2M195.6 83.8h15.2M59.7 100.3h2.5M97.8 102.9h3.8M97.8 100.3h3.8M109.2 102.9h10.2M109.2 100.3h10.2M146 100.3v2.6"/>
<path d="M38.1 137.2h6.3M38.1 132.1v2.5h6.3M38.1 139.7h6.3M57.1 137.2h7.7M57.1 134.6h10.2v1.3M57.1 139.7h7.7M85.1 137.2h6.3M85.1 132.1v2.5h6.3M85.1 139.7h6.3M104.1 137.2h7.7M104.1 134.6h10.2v1.3M104.1 139.7h7.7"/>
<path d="M132.1 137.2h6.3M132.1 132.1v2.5h6.3M132.1 139.7h6.3M151.1 137.2h7.6M151.1 134.6h10.2v1.3M151.1 139.7h7.6M179.1 132.1v2.5h6.3M179.1 137.2h6.3M179.1 139.7h6.3M198.1 137.2h7.6M198.1 134.6h10.2v1.3M198.1 139.7h7.6"/>
<path d="M31.7 153.7h12.7M31.7 151.1h12.7M35.6 156.2h8.8M57.1 153.7h8.9M57.1 156.2h8.9M66 149.9v1.2h-8.9M80 153.7h11.4M80 151.1h11.4M82.5 156.2h8.9M104.1 153.7h8.9M104.1 156.2h8.9M113 149.9v1.2h-8.9"/>
<path d="M127 153.7h11.4M127 151.1h11.4M129.5 156.2h8.9M151.1 153.7h8.9M151.1 156.2h8.9M160 149.9v1.2h-8.9M174 153.7h11.4M174 151.1h11.4M176.5 156.2h8.9M198.1 153.7h8.9M198.1 156.2h8.9M207 149.9v1.2h-8.9"/>
<path d="M236.2 148.6h8.9M22.9 186.7h15.2"/>
</g>
<g fill="none" stroke="#000084" stroke-width=".18">
<path d="M46.4 26.1l1.2 1.2M46.4 28.6l1.2 1.2M47.6 26.1l-1.2 1.2M47.6 28.6l-1.2 1.2M195 85.8l1.2 1.2M195 88.3l1.2 1.2M195 90.8l1.2 1.2M195 93.4l1.2 1.2M195 95.9l1.2 1.2M195 98.5l1.2 1.2M196.2 85.8l-1.2 1.2M196.2 88.3l-1.2 1.2"/>
<path d="M196.2 90.8l-1.2 1.2M196.2 93.4l-1.2 1.2M196.2 95.9l-1.2 1.2M196.2 98.5l-1.2 1.2M195 103.5l1.2 1.2M195 101l1.2 1.2M196.2 103.5l-1.2 1.2M196.2 101l-1.2 1.2"/>
</g>
<path d="M221 133.4h36.8v20.3h-36.8z" fill="none" stroke="#0000c2" stroke-width=".18" stroke-dasharray="1.7 .6"/>
<g fill="none" stroke="#0000c2" stroke-width=".18">
<path d="M12.7 12.7h271.8v33h-271.8zM19 14.6h.3v.2l-.2 .2h-.2M19 14.1l.3 .1M43.5 15.5h.4M43.8 16.3h.1M80.9 15.5h.5M81.2 16.3h.2M91.2 16.3h.1M91.4 15.5l-.2 .2 .2 .2M98.8 16.3h.8M98.8 15.4l.4-.3v1.2M103.2 15.5h.5"/>
<path d="M103.7 15.1h-.3M106.8 16.3l.5-1.2 .4 1.2M107 16h.6M113.9 16.6l.2 .2M114.1 14.9l-.2 .2M114.8 15.5l-.3 .2v.4l.3 .2M53.3 25.6a1.49 1.49 0 0 1 0 1.8M12.7 47h271.8v73.7h-271.8zM23.8 48.4v1l-.3 .3-.3-.1M23.8 48.5l-.4-.1-.2 .3 .1 .5h.5M93.9 50.6h.2M182.9 49.8l.1 .3-.6 .1"/>
<path d="M183 50.6h-.1M183.6 49.8v.8M184 49.8l-.4 .2M260.5 49.8v.8M260.5 49.9l.2-.1h.3v.8M12.7 121.9h271.8v43.2h-271.8zM20.3 123.7l.5 .3-.1 .1-.4 .1M20.3 123.4h.4M228.2 138.9v.8M228.3 139l-.1 .1M234.4 137.6h.5M234.4 136.9l.3-.1 .2 .3-.6 .1"/>
<path d="M247 136.8l.4 .2v.7M247.8 136.8h.5M248 136.4v1.1l.3 .2M12.7 166.4h162.6v30.5h-162.6zM18.6 167.8h.1M33.4 171.2l.2 .1 .3-.1M33.9 170.4v1.1l-.2 .2-.3-.1M33.9 170.5l-.3-.1-.2 .1"/>
</g>
<path d="M95.5 77.1h.7M95.5 99.9h.7M176.8 91h.7M194.6 80.9h.7" fill="none" stroke="#a90000" stroke-width=".18"/>
<g fill="#009600" stroke="#009600" stroke-width=".18">
<circle cx="218.4" cy="68.6" r=".46"/>
<circle cx="218.4" cy="76.2" r=".46"/>
<circle cx="218.4" cy="71.1" r=".46"/>
<circle cx="218.4" cy="73.7" r=".46"/>
<circle cx="240" cy="73.7" r=".46"/>
<circle cx="218.4" cy="81.3" r=".46"/>
<circle cx="218.4" cy="78.7" r=".46"/>
<circle cx="218.4" cy="66" r=".46"/>
<circle cx="146" cy="102.9" r=".46"/>
<circle cx="152.4" cy="40.6" r=".46"/>
<circle cx="170.2" cy="40.6" r=".46"/>
<circle cx="167.6" cy="38.1" r=".46"/>
<circle cx="161.3" cy="40.6" r=".46"/>
<circle cx="158.7" cy="38.1" r=".46"/>
<circle cx="149.9" cy="38.1" r=".46"/>
<circle cx="147.3" cy="35.6" r=".46"/>
<circle cx="156.2" cy="35.6" r=".46"/>
<circle cx="163.8" cy="61" r=".46"/>
<circle cx="146" cy="85.1" r=".46"/>
<circle cx="33" cy="99.1" r=".46"/>
<circle cx="59.7" cy="100.3" r=".46"/>
<circle cx="33" cy="81.3" r=".46"/>
<circle cx="47" cy="72.4" r=".46"/>
<circle cx="47" cy="57.2" r=".46"/>
<circle cx="47" cy="69.9" r=".46"/>
<circle cx="59.7" cy="97.8" r=".46"/>
<circle cx="61" cy="24.1" r=".46"/>
<circle cx="27.9" cy="186.7" r=".46"/>
<circle cx="30.5" cy="186.7" r=".46"/>
<circle cx="33" cy="186.7" r=".46"/>
<circle cx="266.7" cy="63.5" r=".46"/>
<circle cx="243.8" cy="63.5" r=".46"/>
<circle cx="264.2" cy="63.5" r=".46"/>
<circle cx="240" cy="63.5" r=".46"/>
<circle cx="254" cy="73.7" r=".46"/>
</g>
<use href="#words"/>
</svg>
